VERSION 5.7 ;
  NOWIREEXTENSIONATPIN ON ;
  DIVIDERCHAR "/" ;
  BUSBITCHARS "[]" ;
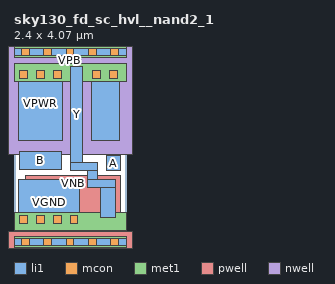
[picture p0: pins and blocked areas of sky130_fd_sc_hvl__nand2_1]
MACRO sky130_fd_sc_hvl__nand2_1
  CLASS BLOCK ;
  FOREIGN sky130_fd_sc_hvl__nand2_1 ;
  ORIGIN 0.000 0.000 ;
  SIZE 2.400 BY 4.070 ;
  PIN A
    ANTENNAGATEAREA 1.125000 ;
    PORT
      LAYER li1 ;
        RECT 1.975 1.525 2.275 1.855 ;
    END
  END A
  PIN B
    ANTENNAGATEAREA 1.125000 ;
    PORT
      LAYER li1 ;
        RECT 0.125 1.550 1.015 1.935 ;
    END
  END B
  PIN VGND
    USE GROUND ;
    PORT
      LAYER li1 ;
        RECT 0.090 0.365 1.400 1.345 ;
      LAYER mcon ;
        RECT 0.120 0.395 0.290 0.565 ;
        RECT 0.480 0.395 0.650 0.565 ;
        RECT 0.840 0.395 1.010 0.565 ;
        RECT 1.200 0.395 1.370 0.565 ;
      LAYER met1 ;
        RECT 0.000 0.255 2.400 0.625 ;
    END
  END VGND
  PIN VNB
    ANTENNADIFFAREA 0.408000 ;
    PORT
      LAYER pwell ;
        RECT 0.250 0.215 2.290 1.435 ;
        RECT -0.130 -0.215 2.530 0.215 ;
      LAYER li1 ;
        RECT 0.000 -0.085 2.400 0.085 ;
      LAYER mcon ;
        RECT 0.155 -0.085 0.325 0.085 ;
        RECT 0.635 -0.085 0.805 0.085 ;
        RECT 1.115 -0.085 1.285 0.085 ;
        RECT 1.595 -0.085 1.765 0.085 ;
        RECT 2.075 -0.085 2.245 0.085 ;
      LAYER met1 ;
        RECT 0.000 -0.115 2.400 0.115 ;
    END
  END VNB
  PIN VPB
    ANTENNADIFFAREA 0.408000 ;
    PORT
      LAYER nwell ;
        RECT -0.330 1.885 2.730 4.485 ;
      LAYER li1 ;
        RECT 0.000 3.985 2.400 4.155 ;
      LAYER mcon ;
        RECT 0.155 3.985 0.325 4.155 ;
        RECT 0.635 3.985 0.805 4.155 ;
        RECT 1.115 3.985 1.285 4.155 ;
        RECT 1.595 3.985 1.765 4.155 ;
        RECT 2.075 3.985 2.245 4.155 ;
      LAYER met1 ;
        RECT 0.000 3.955 2.400 4.185 ;
    END
  END VPB
  PIN VPWR
    USE POWER ;
    PORT
      LAYER li1 ;
        RECT 0.090 2.175 1.040 3.755 ;
        RECT 1.660 2.175 2.250 3.755 ;
      LAYER mcon ;
        RECT 0.120 3.505 0.290 3.675 ;
        RECT 0.480 3.505 0.650 3.675 ;
        RECT 0.840 3.505 1.010 3.675 ;
        RECT 1.690 3.505 1.860 3.675 ;
        RECT 2.050 3.505 2.220 3.675 ;
      LAYER met1 ;
        RECT 0.000 3.445 2.400 3.815 ;
    END
  END VPWR
  PIN Y
    ANTENNADIFFAREA 0.633750 ;
    PORT
      LAYER li1 ;
        RECT 1.220 1.695 1.470 3.755 ;
        RECT 1.220 1.525 1.795 1.695 ;
        RECT 1.580 1.345 1.795 1.525 ;
        RECT 1.580 1.175 2.180 1.345 ;
        RECT 1.850 0.515 2.180 1.175 ;
    END
  END Y
END sky130_fd_sc_hvl__nand2_1
END LIBRARY

